VERSION 5.7 ;
  NOWIREEXTENSIONATPIN ON ;
  DIVIDERCHAR "/" ;
  BUSBITCHARS "[]" ;
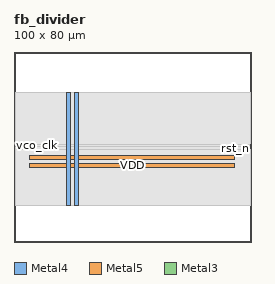
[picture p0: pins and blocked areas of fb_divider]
MACRO fb_divider
  CLASS BLOCK ;
  FOREIGN fb_divider ;
  ORIGIN 0.000 0.000 ;
  SIZE 100.000 BY 80.000 ;
  PIN VDD
    DIRECTION INOUT ;
    USE POWER ;
    PORT
      LAYER Metal4 ;
        RECT 22.240 15.380 23.840 63.020 ;
    END
    PORT
      LAYER Metal5 ;
        RECT 6.720 31.530 92.960 33.130 ;
    END
  END VDD
  PIN VSS
    DIRECTION INOUT ;
    USE GROUND ;
    PORT
      LAYER Metal4 ;
        RECT 25.540 15.380 27.140 63.020 ;
    END
    PORT
      LAYER Metal5 ;
        RECT 6.720 34.830 92.960 36.430 ;
    END
  END VSS
  PIN fb_clk
    DIRECTION OUTPUT ;
    USE SIGNAL ;
    ANTENNADIFFAREA 0.897600 ;
    PORT
      LAYER Metal3 ;
        RECT 99.440 40.320 100.000 40.880 ;
    END
  END fb_clk
  PIN rst_n
    DIRECTION INPUT ;
    USE SIGNAL ;
    ANTENNAGATEAREA 0.498500 ;
    PORT
      LAYER Metal3 ;
        RECT 99.440 39.200 100.000 39.760 ;
    END
  END rst_n
  PIN vco_clk
    DIRECTION INPUT ;
    USE SIGNAL ;
    ANTENNAGATEAREA 4.738000 ;
    PORT
      LAYER Metal3 ;
        RECT 0.000 40.320 0.560 40.880 ;
    END
  END vco_clk
  OBS
      LAYER Nwell ;
        RECT 6.290 15.250 93.390 63.150 ;
      LAYER Metal1 ;
        RECT 6.720 15.380 92.960 63.020 ;
      LAYER Metal2 ;
        RECT 22.380 15.490 91.140 62.910 ;
      LAYER Metal3 ;
        RECT 0.560 41.180 99.440 62.860 ;
        RECT 0.860 40.020 99.140 41.180 ;
        RECT 0.560 38.900 99.140 40.020 ;
        RECT 0.560 15.540 99.440 38.900 ;
  END
END fb_divider
END LIBRARY

